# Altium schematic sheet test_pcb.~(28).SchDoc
size A4; SheetNumber: 1; SheetTotal: 1

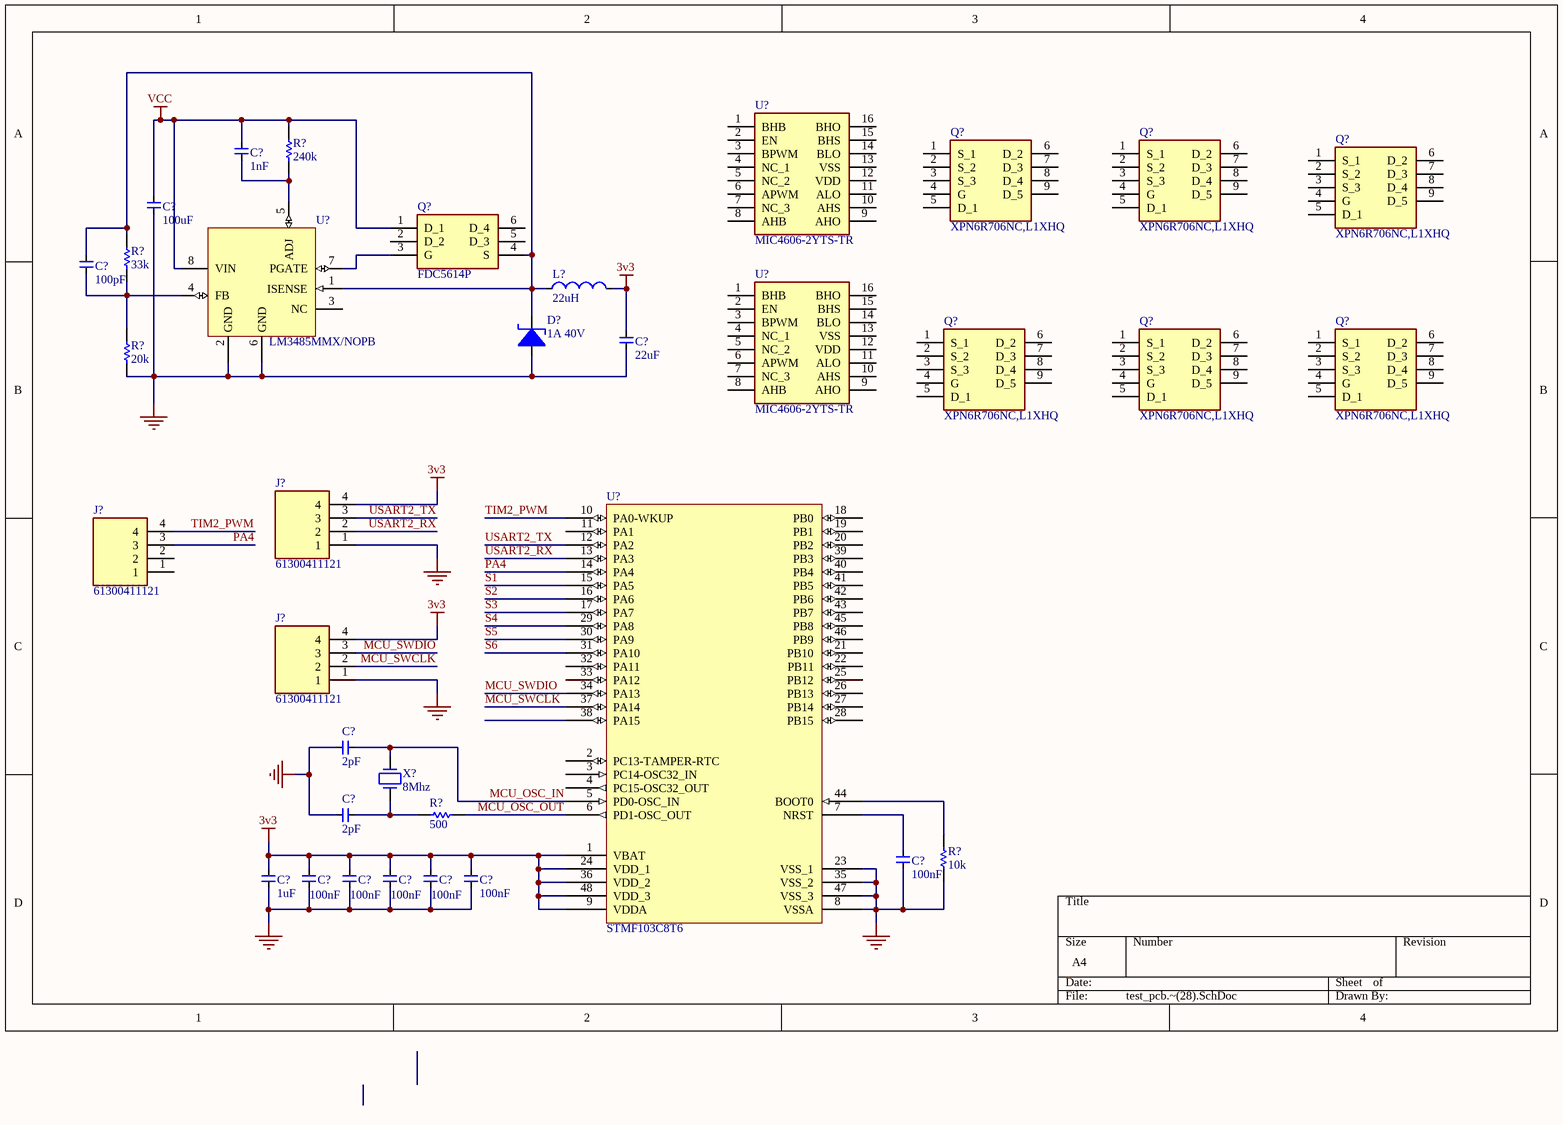
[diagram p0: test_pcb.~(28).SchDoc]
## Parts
(Parts that share a designator on the sheet are numbered #1, #2 ... from top to bottom, then left to right.)
C?#1  1nF  [C0402C104J4RACTU]
C?#2  100uF  [GRM31x]
C?#3  100pF
C?#4  22uF  [CAPC2012X145N]
C?#5  2pF
C?#6  2pF
C?#7  100nF
C?#8  1uF
C?#9  100nF
C?#10  100nF
C?#11  100nF
C?#12  100nF
C?#13  100nF
D?  1A 40V  [DIOM5026X262N]
J?#1  61300411121
J?#2  61300411121
J?#3  61300411121
L?  22uH  [INDPM7166X300N]
Q?#1  XPN6R706NC,L1XHQ  [XPN6R706NCL1XHQ]
Q?#2  XPN6R706NC,L1XHQ  [XPN6R706NCL1XHQ]
Q?#3  XPN6R706NC,L1XHQ  [XPN6R706NCL1XHQ]
Q?#4  FDC5614P  [SOT95P280X110-6N]
Q?#5  XPN6R706NC,L1XHQ  [XPN6R706NCL1XHQ]
Q?#6  XPN6R706NC,L1XHQ  [XPN6R706NCL1XHQ]
Q?#7  XPN6R706NC,L1XHQ  [XPN6R706NCL1XHQ]
R?#1  240k  [ERJ3EKF1000V]
R?#2  33k  [ERA3AEB101V]
R?#3  20k  [ERJ2RKD1004X]
R?#4  500
R?#5  10k
U?#1  MIC4606-2YTS-TR  [SOP65P640X120-16N]
U?#2  LM3485MMX/NOPB  [SOP65P490X110-8N]
U?#3  MIC4606-2YTS-TR  [SOP65P640X120-16N]
U?#4  STMF103C8T6
X?  8Mhz

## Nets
3v3: C?#4.2 C?#8.2 C?#9.2 C?#10.2 C?#11.2 C?#12.2 C?#13.2 J?#1.4 J?#3.4 L?.2 U?#4.1(VBAT) U?#4.9(VDDA) U?#4.24(VDD_1) U?#4.36(VDD_2) U?#4.48(VDD_3)
GND: C?#2.1 C?#4.1 C?#5.1 C?#6.1 C?#7.1 C?#8.1 C?#9.1 C?#10.1 C?#11.1 C?#12.1 C?#13.1 D?.+ J?#1.1 J?#3.1 R?#3.4 R?#5.4 U?#2.2(GND) U?#2.6(GND) U?#4.8(VSSA) U?#4.23(VSS_1) U?#4.35(VSS_2) U?#4.47(VSS_3)
VCC: C?#1.2 C?#2.2 Q?#4.1(D_1) R?#1.2 U?#2.8(VIN)
MCU_OSC_IN: C?#5.2 U?#4.5(PD0-OSC_IN) X?.2
MCU_OSC_OUT: R?#4.2 U?#4.6(PD1-OSC_OUT)
MCU_SWCLK: J?#3.2 U?#4.37(PA14)
MCU_SWDIO: J?#3.3 U?#4.34(PA13)
PA4: J?#2.3 U?#4.14(PA4)
S1: U?#4.15(PA5)
S2: U?#4.16(PA6)
S3: U?#4.17(PA7)
S4: U?#4.29(PA8)
S5: U?#4.30(PA9)
S6: U?#4.31(PA10)
TIM2_PWM: J?#2.4 U?#4.10(PA0-WKUP)
USART2_RX: J?#1.2 U?#4.13(PA3)
USART2_TX: J?#1.3 U?#4.12(PA2)
NetC?#1_1: C?#1.1 R?#1.4 U?#2.5(ADJ)
NetC?#3_1: C?#3.1 R?#2.4 R?#3.2 U?#2.4(FB)
NetC?#3_2: C?#3.2 D?.- L?.1 Q?#4.4(S) R?#2.2 U?#2.1(ISENSE)
NetC?#6_2: C?#6.2 R?#4.4 X?.1
NetC?#7_2: C?#7.2 U?#4.7(NRST)
NetQ?#4_3: Q?#4.3(G) U?#2.7(PGATE)
NetR?#5_2: R?#5.2 U?#4.44(BOOT0)

Not connected (* = marked no-connect by the designer): J?#2 1 2; Q?#1 1(S_1) 2(S_2) 3(S_3) 4(G) 5(D_1) 6(D_2) 7(D_3) 8(D_4) 9(D_5); Q?#2 1(S_1) 2(S_2) 3(S_3) 4(G) 5(D_1) 6(D_2) 7(D_3) 8(D_4) 9(D_5); Q?#3 1(S_1) 2(S_2) 3(S_3) 4(G) 5(D_1) 6(D_2) 7(D_3) 8(D_4) 9(D_5); Q?#4 2(D_2) 5(D_3) 6(D_4); Q?#5 1(S_1) 2(S_2) 3(S_3) 4(G) 5(D_1) 6(D_2) 7(D_3) 8(D_4) 9(D_5); Q?#6 1(S_1) 2(S_2) 3(S_3) 4(G) 5(D_1) 6(D_2) 7(D_3) 8(D_4) 9(D_5); Q?#7 1(S_1) 2(S_2) 3(S_3) 4(G) 5(D_1) 6(D_2) 7(D_3) 8(D_4) 9(D_5); U?#1 1(BHB) 2(EN) 3(BPWM) 4(NC_1) 5(NC_2) 6(APWM) 7(NC_3) 8(AHB) 9(AHO) 10(AHS) 11(ALO) 12(VDD) 13(VSS) 14(BLO) 15(BHS) 16(BHO); U?#2 3(NC); U?#3 1(BHB) 2(EN) 3(BPWM) 4(NC_1) 5(NC_2) 6(APWM) 7(NC_3) 8(AHB) 9(AHO) 10(AHS) 11(ALO) 12(VDD) 13(VSS) 14(BLO) 15(BHS) 16(BHO); U?#4 2(PC13-TAMPER-RTC) 3(PC14-OSC32_IN) 4(PC15-OSC32_OUT) 11(PA1) 18(PB0) 19(PB1) 20(PB2) 21(PB10) 22(PB11) 25(PB12) 26(PB13) 27(PB14) 28(PB15) 32(PA11) 33(PA12) 38(PA15) 39(PB3) 40(PB4) 41(PB5) 42(PB6) 43(PB7) 45(PB8) 46(PB9)

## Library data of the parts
C?#1 = C0402C102J5GECTU: Ceramic Capacitor, Multilayer, Ceramic, 50V, 5% +Tol, 5% -Tol, C0G, -/+30ppm/Cel TC, 0.001uF, Surface Mount, 0402; Manufacturer: KEMET
C?#2 = GRM31CR60J107MEA8K: Ceramic Capacitor, Multilayer, Ceramic, 6.3V, 20% +Tol, 20% -Tol, X5R, 15% TC, 100uF, Surface Mount, 1206; Manufacturer: Murata
C?#3 = GRM0335C1H101JA01D: Ceramic Capacitor, Multilayer, Ceramic, 50V, 5% +Tol, 5% -Tol, C0G, 30ppm/Cel TC, 0.0001uF, Surface Mount, 0201; Manufacturer: Murata; Multilayer: Yes
C?#4 = C2012X5R1V226M125AC: Ceramic Capacitor, Multilayer, Ceramic, 35V, 20% +Tol, 20% -Tol, X5R, 15% TC, 22uF, Surface Mount, 0805; Manufacturer: TDK; Multilayer: Yes
C?#5 C?#6 = GJM0335C1E2R0BB01D: Ceramic Capacitor, Multilayer, Ceramic, 25V, 5% +Tol, 5% -Tol, C0G, 30ppm/Cel TC, 0.000002uF, Surface Mount, 0201; Manufacturer: Murata; Multilayer: Yes
C?#7 C?#9-C?#13 = GRM033C80J104KE15D: Ceramic Capacitor, Multilayer, Ceramic, 6.3V, 10% +Tol, 10% -Tol, X6S, 22% TC, 0.1uF, Surface Mount, 0201; Manufacturer: Murata; Multilayer: Yes
C?#8 = GRM033R60J105MEA2D: Ceramic Capacitor, Multilayer, Ceramic, 6.3V, 20% +Tol, 20% -Tol, X5R, 15% TC, 1uF, Surface Mount, 0201; Manufacturer: Murata; Multilayer: Yes
D? = SS14: Rectifier Diode, Schottky, 1 Phase, 1 Element, 1A, 40V V(RRM), Silicon, DO-214AC; Manufacturer: ON Semiconductor / Fairchild; Package Body Material: Plastic; Forward Voltage: 500mV; Non-rep Pk Forward Current-Max: 30A; Number of Elements: 1; Additional Feature: FREE WHEELING DIODE; Max Power Dissipation: 1.1W; Qualification Status: Not Qualified
L? = ECS-MPIL0630-220MC: General Purpose Inductor, 22uH, 20%, 1 Element, Ferrite-Core, SMD, 2826; Manufacturer: ECS International
Q?#1-Q?#3 Q?#5-Q?#7 = XPN6R706NC,L1XHQ: Mosfet N-ch 60V 40A 8TSON; Manufacturer: Toshiba
Q?#4 = FDC5614P: Small Signal Field-Effect Transistor, 3A I(D), 60V, 1-Element, P-Channel, Silicon, Metal-oxide Semiconductor FET; Manufacturer: ON Semiconductor / Fairchild; Package Body Material: Plastic; Drain-source On Resistance-Max: 105mR; Number of Elements: 1; Operating Mode: ENHANCEMENT MODE; Power Dissipation-Max (Abs): 1.6W; Transistor Application: SWITCHING; Qualification Status: Not Qualified
R?#1 = ERJ-3GEYJ244V: Fixed Resistor, Metal Glaze/thick Film, 0.1W, 240000ohm, 75V, 5% +/-Tol, 200ppm/Cel, Surface Mount, 0603; Manufacturer: Panasonic; Power: 100mW; Rated Temperature: 70°C; Value: 240kR; Temperature Coefficient (ppm/Cel): 200; Package Height: 0.45mm; Package Length: 1.6mm; Package Width: 0.8mm; Reference Standard: AEC-Q200
R?#2 = ERA-3AEB333V: Fixed Resistor, Thin Film, 0.1W, 33000ohm, 75V, 0.1% +/-Tol, 25ppm/Cel, Surface Mount, 0603; Manufacturer: Panasonic; Power: 100mW; Rated Temperature: 85°C; Value: 33kR; Temperature Coefficient (ppm/Cel): 25; Package Height: 0.45mm; Package Length: 1.6mm; Package Width: 0.8mm; Reference Standard: AEC-Q200
R?#3 = ERJ-2RKF2002X: Fixed Resistor, Metal Glaze/thick Film, 0.1W, 20000ohm, 50V, 1% +/-Tol, 100ppm/Cel, Surface Mount, 0402; Manufacturer: Panasonic; Power: 100mW; Rated Temperature: 70°C; Value: 20kR; Temperature Coefficient (ppm/Cel): 100; Package Height: 0.35mm; Package Length: 1mm; Package Width: 0.5mm; Reference Standard: AEC-Q200
R?#4 = ERA-2AEB4990X: Fixed Resistor, Thin Film, 0.063W, 499ohm, 50V, 0.1% +/-Tol, 25ppm/Cel, Surface Mount, 0402; Manufacturer: Panasonic; Power: 63mW; Rated Temperature: 85°C; Value: 499R; Working Voltage: 25V; Temperature Coefficient (ppm/Cel): 25; Package Height: 0.35mm; Package Length: 1mm; Package Width: 0.5mm; Reference Standard: AEC-Q200
R?#5 = RNCP1206FTD10K0: Fixed Resistor, Thin Film, 0.5W, 10000ohm, 200V, 1% +/-Tol, 100ppm/Cel, Surface Mount, 1206; Manufacturer: Stackpole Electronics; Additional Feature: ANTI-SULFUR; Power: 500mW; Rated Temperature: 70°C; Value: 10kR; Temperature Coefficient (ppm/Cel): 100; Package Height: 0.5mm; Package Length: 3.1mm; Package Width: 1.5mm
U?#1 U?#3 = MIC4606-2YTS-TR: Full Bridge Based MOSFET Driver, 1A, PDSO16; Manufacturer: Microchip
U?#2 = LM3485MMX/NOPB: Switching Controller, Voltage-mode, 0.1A, 1000kHz Switching Freq-Max, PDSO8; Manufacturer: TI National Semiconductor; Package Body Material: Plastic; Control Technique: HYSTERETIC CURRENT MODE; Max Supply Voltage: 35V; Min Input Voltage: 4.5V; Nominal Supply Voltage: 12V; Channels: 1; Max Output current: 100mA; Package Equivalence Code: TSSOP8,.19; Switcher Configuration: SINGLE; Frequency: 1MHz; Time @ Peak Reflow Temperature-Max (s): 40s; Qualification Status: Not Qualified
U?#4 = STM32F103C8T6_1: ARM Cortex-M3 STM32 F1 Microcontroller 32-Bit 72MHz 64kB FLASH LQFP48 STM32F103C8T6; Manufacturer: STMicroelectronics; Package Body Material: Plastic; Clock Frequency: 16MHz; Number of I/O Lines: 37; Package Equivalence Code: QFP48,.35SQ,20; Power Supplies: 2.5/3.3; Max Supply Current: 50mA; Max Supply Voltage: 3.6V; Min Supply Voltage: 2V; Nominal Supply Voltage: 3.3V; Time @ Peak Reflow Temperature-Max (s): 30s; Peripherals: POR; Interface: I2C; Qualification Status: Not Qualified
X? = H130A-8.000-8-2030-TR: Parallel - Fundamental Quartz Crystal, 8MHz Min, 150MHz Max, 8MHz Nom; Manufacturer: Raltron Electronics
